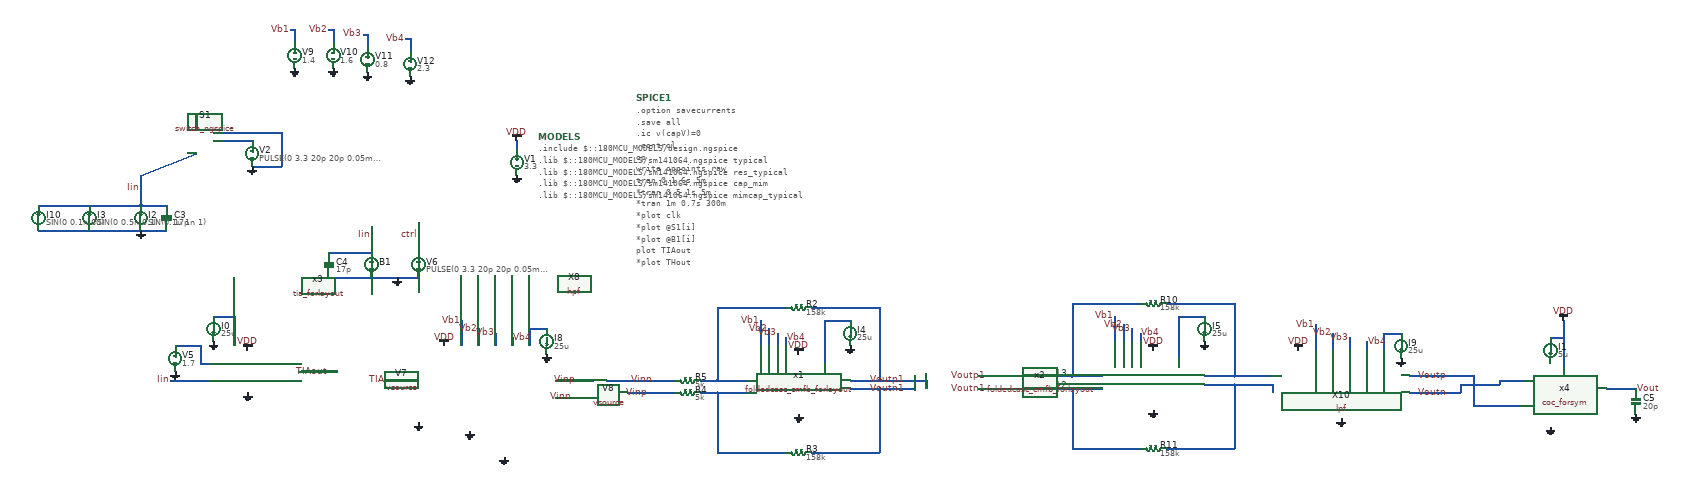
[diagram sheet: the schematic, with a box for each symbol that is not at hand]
v {xschem version=3.4.8RC file_version=1.3}
G {}
K {}
V {}
S {}
F {}
E {}
N 840 -1130 840 -1110 {lab=VDD}
N 330 -590 370 -590 {lab=TIAout
}
N 130 -720 180 -720 {lab=#net1
}
N 180 -720 180 -650 {lab=#net1
}
N 70 -570 120 -570 {lab=Iin
}
N 370 -590 420 -590 {lab=TIAout
}
N 30 -570 70 -570 {lab=Iin
}
N 40 -650 100 -650 {lab=#net2
}
N -40 -1010 -40 -980 {lab=Iin
}
N -40 -980 20 -980 {lab=Iin
}
N -40 -920 20 -920 {lab=0
}
N -40 -1050 -40 -1010 {lab=Iin
}
N 130 -1130 220 -1130 {lab=#net3
spice_ignore=true}
N 130 -1150 290 -1150 {lab=0
spice_ignore=true}
N 220 -1070 290 -1070 {lab=0
spice_ignore=true}
N 290 -1150 290 -1070 {lab=0
spice_ignore=true}
N -160 -980 -40 -980 {lab=Iin
}
N -160 -920 -40 -920 {lab=0
}
N -40 -1050 90 -1100 {lab=Iin
spice_ignore=true}
N 90 -1190 90 -1160 {lab=#net4
spice_ignore=true}
N 1620 -550 1690 -550 {lab=Voutn1
}
N 1690 -550 1690 -400 {lab=Voutn1
}
N 1310 -540 1380 -540 {lab=#net3
}
N 1310 -570 1380 -570 {lab=#net4
}
N 1310 -740 1310 -590 {lab=#net4
}
N 1620 -570 1690 -570 {lab=Voutp1
}
N 1690 -740 1690 -570 {lab=Voutp1
}
N 1690 -570 1800 -570 {lab=Voutp1
}
N 1690 -550 1770 -550 {lab=Voutn1
}
N 1410 -710 1410 -650 {lab=Vb1
}
N 1430 -690 1430 -650 {lab=Vb2
}
N 1530 -740 1690 -740 {lab=Voutp1
}
N 1310 -740 1470 -740 {lab=#net4
}
N 1530 -400 1690 -400 {lab=Voutn1
}
N 1310 -400 1470 -400 {lab=#net3
}
N 1270 -570 1310 -570 {lab=#net4
}
N 1270 -540 1310 -540 {lab=#net3
}
N 1310 -590 1310 -570 {lab=#net4
}
N 1310 -540 1310 -400 {lab=#net3
}
N 1450 -680 1450 -650 {lab=Vb3
}
N 1470 -670 1470 -650 {lab=Vb4
}
N 1560 -710 1560 -610 {lab=#net5
}
N 1560 -710 1620 -710 {lab=#net5
}
N 1800 -570 1800 -550 {lab=Voutp1
}
N 1770 -580 1770 -550 {lab=Voutn1
}
N 2450 -560 2520 -560 {lab=#net6
}
N 2520 -560 2520 -410 {lab=#net6
}
N 2140 -550 2210 -550 {lab=#net7
}
N 2140 -580 2210 -580 {lab=#net8
}
N 2140 -750 2140 -600 {lab=#net8
}
N 2450 -580 2520 -580 {lab=#net9
}
N 2520 -750 2520 -580 {lab=#net9
}
N 2240 -720 2240 -660 {lab=Vb1
}
N 2260 -700 2260 -660 {lab=Vb2
}
N 2360 -750 2520 -750 {lab=#net9
}
N 2140 -750 2300 -750 {lab=#net8
}
N 2360 -410 2520 -410 {lab=#net6
}
N 2140 -410 2300 -410 {lab=#net7
}
N 2100 -580 2140 -580 {lab=#net8
}
N 2100 -550 2140 -550 {lab=#net7
}
N 2000 -550 2040 -550 {lab=Voutn1
}
N 2140 -600 2140 -580 {lab=#net8
}
N 2140 -550 2140 -410 {lab=#net7
}
N 2280 -690 2280 -660 {lab=Vb3
}
N 2300 -680 2300 -660 {lab=Vb4
}
N 2390 -720 2390 -620 {lab=#net10
}
N 2390 -720 2450 -720 {lab=#net10
}
N 2000 -580 2040 -580 {lab=Voutp1
}
N 2520 -580 2610 -580 {lab=#net9
}
N 2520 -560 2610 -560 {lab=#net6
}
N 1920 -580 2000 -580 {lab=Voutp1
}
N 1920 -550 2000 -550 {lab=Voutn1
}
N 320 -1390 320 -1360 {lab=Vb1
}
N 310 -1390 320 -1390 {lab=Vb1
}
N 410 -1390 410 -1360 {lab=Vb2
}
N 400 -1390 410 -1390 {lab=Vb2
}
N 490 -1380 490 -1350 {lab=Vb3
}
N 480 -1380 490 -1380 {lab=Vb3
}
N 590 -1370 590 -1340 {lab=Vb4
}
N 580 -1370 590 -1370 {lab=Vb4
}
N 1100 -570 1210 -570 {lab=Vinn
}
N 1100 -540 1210 -540 {lab=Vinp
}
N 500 -810 610 -810 {lab=0
spice_ignore=true}
N 610 -940 610 -870 {lab=ctrl
spice_ignore=true}
N 500 -930 500 -870 {lab=Iin
spice_ignore=true}
N 400 -870 500 -870 {lab=Iin
spice_ignore=true}
N 400 -810 500 -810 {lab=0
spice_ignore=true}
N 1050 -570 1100 -570 {lab=Vinn}
N 2930 -580 2980 -580 {lab=Voutp}
N 2930 -540 2980 -540 {lab=Voutn}
N 2980 -580 3050 -580 {lab=Voutp}
N 2980 -540 3050 -540 {lab=Voutn}
N 3290 -660 3290 -600 {lab=VDD}
N 3390 -550 3460 -550 {lab=Vout}
N 3140 -570 3200 -570 {lab=Voutn}
N 3110 -510 3190 -510 {lab=Voutp}
N 3050 -580 3080 -580 {lab=Voutp}
N 3080 -580 3080 -540 {lab=Voutp}
N 3050 -560 3050 -540 {lab=Voutn}
N 3050 -560 3140 -560 {lab=Voutn}
N 530 -570 610 -570 {lab=TIAout}
N 930 -570 1020 -570 {lab=Vinp}
N 930 -530 1010 -530 {lab=Vinn}
N 710 -710 710 -650 {lab=Vb1
}
N 750 -690 750 -650 {lab=Vb2
}
N 790 -680 790 -650 {lab=Vb3
}
N 830 -670 830 -650 {lab=Vb4
}
N 870 -690 870 -650 {lab=#net11}
N 870 -690 910 -690 {lab=#net11}
N 2610 -560 2610 -540 {lab=#net6}
N 2710 -700 2710 -640 {lab=Vb1
}
N 2750 -680 2750 -640 {lab=Vb2
}
N 2790 -670 2790 -640 {lab=Vb3
}
N 2830 -660 2830 -640 {lab=Vb4
}
N 2870 -680 2870 -640 {lab=#net12}
N 2870 -680 2910 -680 {lab=#net12}
N -280 -980 -160 -980 {lab=Iin
}
N -280 -920 -160 -920 {lab=0
}
N 3080 -540 3080 -510 {lab=Voutp}
N 3080 -510 3110 -510 {lab=Voutp}
N 3140 -570 3140 -560 {lab=Voutn}
N 3260 -670 3290 -670 {lab=VDD}
N 3290 -670 3290 -660 {lab=VDD}
N 3290 -710 3290 -670 {lab=VDD}
N 100 -650 100 -610 {lab=#net2}
N 100 -610 120 -610 {lab=#net2}
C {vsource.sym} 840 -1080 0 0 {name=V1 value=3.3 savecurrent=false}
C {vdd.sym} 840 -1130 0 0 {name=l6 lab=VDD}
C {gnd.sym} 840 -1050 0 0 {name=l11 lab=0}
C {code_shown.sym} 1120 -1230 0 0 {name=SPICE1 only_toplevel=false value=".option savecurrents
.save all
.ic v(capV)=0
.control
op
write oppoints.raw
tran 0.1 6s 5m
*tran 0.5 1s 5m
*tran 1m 0.7s 300m
*plot clk
*plot @S1[i]
*plot @B1[i]
plot TIAout
*plot THout
plot Vinp Vinn
plot Voutp1 Voutn1
plot Voutp Voutn
plot Vout
.endc"
}
C {isource.sym} 130 -690 0 0 {name=I0 value=25u
}
C {gnd.sym} 130 -660 0 0 {name=l9 lab=0
}
C {vdd.sym} 210 -640 0 0 {name=l10 lab=VDD
}
C {gnd.sym} 210 -540 0 0 {name=l12 lab=0
}
C {lab_pin.sym} 30 -570 0 0 {name=p1 sig_type=std_logic lab=Iin
spice_ignore=short}
C {gnd.sym} -40 -920 0 0 {name=l31 lab=0
}
C {lab_pin.sym} -40 -1020 0 0 {name=p11 sig_type=std_logic lab=Iin
}
C {capa.sym} 20 -950 0 0 {name=C3
m=1
value=17p
footprint=1206
device="ceramic capacitor"
}
C {isource.sym} -40 -950 2 0 {name=I2 value="SIN(0.1u 1n 1)"
}
C {lab_pin.sym} 400 -590 1 0 {name=p2 sig_type=std_logic lab=TIAout
}
C {vsource.sym} 220 -1100 0 0 {name=V2 value="PULSE(0 3.3 20p 20p 0.05m 0.5m)" savecurrent=false
spice_ignore=true}
C {gnd.sym} 220 -1070 0 0 {name=l14 lab=0
spice_ignore=true}
C {isource.sym} -160 -950 2 0 {name=I3 value="SIN(0 0.5n 0.1)"
}
C {switch_ngspice.sym} 90 -1130 2 0 {name=S1 model=SW1
device_model=".MODEL SW1 SW 
+ VT=0.9 VH=0.01
+ RON=1 ROFF=10e6 "
spice_ignore=true}
C {lab_pin.sym} 1430 -690 3 1 {name=p6 sig_type=std_logic lab=Vb2
}
C {lab_pin.sym} 1410 -710 0 0 {name=p7 sig_type=std_logic lab=Vb1
}
C {vdd.sym} 1500 -630 0 0 {name=l15 lab=VDD
}
C {isource.sym} 1620 -680 0 0 {name=I4 value=25u
}
C {gnd.sym} 1500 -490 0 0 {name=l16 lab=0
}
C {res.sym} 1500 -740 1 0 {name=R2
value=158k
footprint=1206
device=resistor
m=1
}
C {res.sym} 1500 -400 1 0 {name=R3
value=158k
footprint=1206
device=resistor
m=1
}
C {res.sym} 1240 -540 1 0 {name=R4
value=5k
footprint=1206
device=resistor
m=1
}
C {res.sym} 1240 -570 1 0 {name=R5
value=5k
footprint=1206
device=resistor
m=1
}
C {lab_pin.sym} 1470 -670 0 1 {name=p8 sig_type=std_logic lab=Vb4
}
C {lab_pin.sym} 1450 -680 3 1 {name=p9 sig_type=std_logic lab=Vb3
}
C {gnd.sym} 1620 -650 0 0 {name=l17 lab=0
}
C {lab_pin.sym} 2260 -700 3 1 {name=p24 sig_type=std_logic lab=Vb2
}
C {lab_pin.sym} 2240 -720 0 0 {name=p25 sig_type=std_logic lab=Vb1
}
C {vdd.sym} 2330 -640 0 0 {name=l24 lab=VDD
}
C {isource.sym} 2450 -690 0 0 {name=I5 value=25u
}
C {gnd.sym} 2330 -500 0 0 {name=l25 lab=0
}
C {res.sym} 2330 -750 1 0 {name=R10
value=158k
footprint=1206
device=resistor
m=1
}
C {res.sym} 2330 -410 1 0 {name=R11
value=158k
footprint=1206
device=resistor
m=1
}
C {res.sym} 2070 -550 1 0 {name=R12
value=5k
footprint=1206
device=resistor
m=1
}
C {res.sym} 2070 -580 1 0 {name=R13
value=5k
footprint=1206
device=resistor
m=1
}
C {lab_pin.sym} 2300 -680 0 1 {name=p26 sig_type=std_logic lab=Vb4
}
C {lab_pin.sym} 2280 -690 3 1 {name=p27 sig_type=std_logic lab=Vb3
}
C {gnd.sym} 2450 -660 0 0 {name=l26 lab=0
}
C {vsource.sym} 320 -1330 0 0 {name=V9 value=1.4 savecurrent=false
}
C {gnd.sym} 320 -1300 0 0 {name=l18 lab=0
}
C {lab_pin.sym} 310 -1390 0 0 {name=p14 sig_type=std_logic lab=Vb1
}
C {vsource.sym} 410 -1330 0 0 {name=V10 value=1.6 savecurrent=false
}
C {gnd.sym} 410 -1300 0 0 {name=l19 lab=0
}
C {lab_pin.sym} 400 -1390 0 0 {name=p15 sig_type=std_logic lab=Vb2
}
C {vsource.sym} 490 -1320 0 0 {name=V11 value=0.8 savecurrent=false
}
C {gnd.sym} 490 -1290 0 0 {name=l20 lab=0
}
C {lab_pin.sym} 480 -1380 0 0 {name=p16 sig_type=std_logic lab=Vb3
}
C {vsource.sym} 590 -1310 0 0 {name=V12 value=2.3 savecurrent=false
}
C {gnd.sym} 590 -1280 0 0 {name=l21 lab=0
}
C {lab_pin.sym} 580 -1370 0 0 {name=p17 sig_type=std_logic lab=Vb4
}
C {lab_pin.sym} 570 -570 1 0 {name=p19 sig_type=std_logic lab=TIAout
}
C {lab_pin.sym} 1160 -570 1 0 {name=p20 sig_type=std_logic lab=Vinn
}
C {lab_pin.sym} 3020 -580 1 0 {name=p21 sig_type=std_logic lab=Voutp
}
C {lab_pin.sym} 3020 -540 3 0 {name=p22 sig_type=std_logic lab=Voutn
}
C {gnd.sym} 40 -590 0 0 {name=l32 lab=0
}
C {vsource.sym} 40 -620 0 0 {name=V5 value=1.7 savecurrent=false
}
C {bsource.sym} 500 -840 0 0 {name=B1 VAR=I FUNC="(0.1u + 1n * sin(2*pi*1*time)) * (v(ctrl) > 1.65 ? 1 : 0)" m=1
spice_ignore=true}
C {vsource.sym} 610 -840 0 0 {name=V6 value="PULSE(0 3.3 20p 20p 0.05m 0.5m)" savecurrent=false
spice_ignore=true}
C {gnd.sym} 560 -810 0 0 {name=l33 lab=0
spice_ignore=true}
C {lab_pin.sym} 500 -910 0 0 {name=p28 sig_type=std_logic lab=Iin
spice_ignore=true}
C {lab_pin.sym} 610 -910 0 0 {name=p29 sig_type=std_logic lab=ctrl
spice_ignore=true}
C {capa.sym} 400 -840 0 0 {name=C4
m=1
value=17p
footprint=1206
device="ceramic capacitor"
spice_ignore=true}
C {gnd.sym} 610 -470 0 0 {name=l34 lab=0
}
C {vsource.sym} 610 -500 0 0 {name=V7 value=1.7 savecurrent=false
}
C {lab_pin.sym} 1750 -570 1 0 {name=p30 sig_type=std_logic lab=Voutp1
}
C {lab_pin.sym} 1750 -550 3 0 {name=p31 sig_type=std_logic lab=Voutn1
}
C {chipathon-2026-ppg/ps-filters/hpf.sym} 770 -550 0 0 {name=X8}
C {gnd.sym} 810 -390 0 0 {name=l35 lab=0
}
C {vsource.sym} 810 -420 0 0 {name=V8 value=1.7 savecurrent=false
}
C {gnd.sym} 3260 -460 0 0 {name=l36 lab=0
}
C {lab_pin.sym} 3460 -550 0 1 {name=p32 sig_type=std_logic lab=Vout
}
C {vdd.sym} 3290 -710 0 0 {name=l37 lab=VDD}
C {lab_pin.sym} 980 -570 1 0 {name=p33 sig_type=std_logic lab=Vinp
}
C {lab_pin.sym} 970 -530 3 0 {name=p34 sig_type=std_logic lab=Vinn
}
C {lab_pin.sym} 1150 -540 3 0 {name=p35 sig_type=std_logic lab=Vinp
}
C {gnd.sym} 730 -450 0 0 {name=l38 lab=0
}
C {vdd.sym} 670 -650 0 0 {name=l39 lab=VDD
}
C {isource.sym} 910 -660 0 0 {name=I8 value=25u
}
C {gnd.sym} 910 -630 0 0 {name=l40 lab=0
}
C {lab_pin.sym} 710 -710 0 0 {name=p4 sig_type=std_logic lab=Vb1
}
C {lab_pin.sym} 750 -690 3 1 {name=p36 sig_type=std_logic lab=Vb2
}
C {lab_pin.sym} 790 -680 3 1 {name=p37 sig_type=std_logic lab=Vb3
}
C {lab_pin.sym} 830 -670 0 1 {name=p38 sig_type=std_logic lab=Vb4
}
C {chipathon-2026-ppg/ps-filters/lpf.sym} 2770 -560 0 0 {name=X10}
C {vdd.sym} 2670 -640 0 0 {name=l41 lab=VDD
}
C {isource.sym} 2910 -650 0 0 {name=I9 value=25u
}
C {lab_pin.sym} 2710 -700 0 0 {name=p39 sig_type=std_logic lab=Vb1
}
C {lab_pin.sym} 2750 -680 3 1 {name=p40 sig_type=std_logic lab=Vb2
}
C {lab_pin.sym} 2790 -670 3 1 {name=p41 sig_type=std_logic lab=Vb3
}
C {lab_pin.sym} 2830 -660 0 1 {name=p42 sig_type=std_logic lab=Vb4
}
C {gnd.sym} 2770 -480 0 0 {name=l42 lab=0
}
C {gnd.sym} 2910 -620 0 0 {name=l43 lab=0
}
C {isource.sym} -280 -950 2 0 {name=I10 value="SIN(0 0.1n 60)"
}
C {capa.sym} 3460 -520 0 0 {name=C5
m=1
value=20p
footprint=1206
device="ceramic capacitor"
}
C {gnd.sym} 3460 -490 0 0 {name=l44 lab=0
}
C {lab_pin.sym} 1940 -580 1 0 {name=p47 sig_type=std_logic lab=Voutp1
}
C {lab_pin.sym} 1940 -550 3 0 {name=p52 sig_type=std_logic lab=Voutn1
}
C {chipathon-2026-ppg/jz_fda2/xschem/foldedcasc_cmfb_forlayout.sym} 1490 -560 0 0 {name=x1}
C {chipathon-2026-ppg/jz_fda2/xschem/foldedcasc_cmfb_forlayout.sym} 2320 -570 0 0 {name=x2}
C {isource.sym} 3260 -640 0 0 {name=I1 value=5u
}
C {chipathon-2026-ppg/comparator/schematic-design/coc_forsym.sym} 3280 -550 0 0 {name=x4}
C {code.sym} 890 -1140 0 0 {name=MODELS only_toplevel=true  
format="tcleval( @value )" 
value="
.include $::180MCU_MODELS/design.ngspice
.lib $::180MCU_MODELS/sm141064.ngspice typical
.lib $::180MCU_MODELS/sm141064.ngspice res_typical
.lib $::180MCU_MODELS/sm141064.ngspice cap_mim
.lib $::180MCU_MODELS/sm141064.ngspice mimcap_typical
"}
C {chipathon-2026-ppg/jz_tia/xschem/tia_forlayout.sym} 270 -590 0 0 {name=x3}
